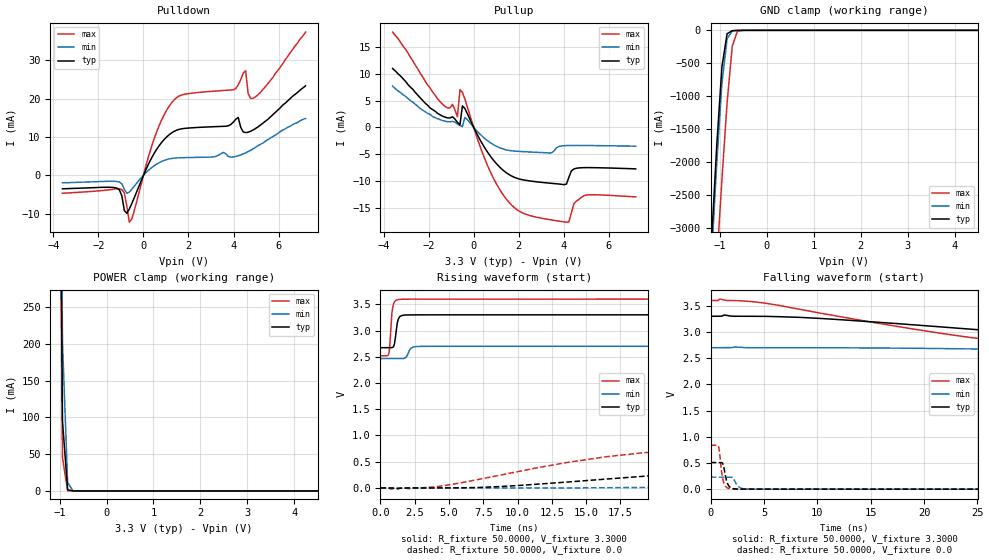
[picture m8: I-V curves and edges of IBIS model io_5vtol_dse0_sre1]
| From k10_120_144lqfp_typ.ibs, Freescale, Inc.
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[Model]  io_5vtol_dse0_sre1
|   Model io_5vtol_dse0_sre1
| Library cells for typ/min/max conditions are connected as defined below:
|  pad - External Pad
|  ipp_do - Core Input
|  ipp_obe - Output Buffer Enable
|  esd_boost - vdd_s_3v
|  esd_bus - vdd_s_3v
|  ipp_ame - vss_s_lv
|  ipp_dse - vss_s_lv
|  ipp_ina40a_5vtol - NC
|  ipp_ina40b_5vtol - NC
|  ipp_ina_5vtol - NC
|  ipp_ina_mux_3v - NC
|  ipp_ind - NC
|  ipp_ind_3v - NC
|  ipp_pue - vss_s_lv
|  ipp_sre - vdd_s_lv
|  tie_3v - vdd_s_3v
|  tie_hi - vdd_s_lv
|  vbuf_3v - vdd_s_3v
|  vdd_bulk_lv - vdd_s_lv
|  vdd_s_3v - vdd_s_3v
|  vdd_s_lv - vdd_s_lv
|  vss_bulk - vss_s_3v
|  vss_s_3v - vss_s_3v
|  vss_s_lv - vss_s_lv
| All other pins connected to ground
Model_type I/O
Polarity   Non-Inverting
Enable   Active-High
Vinl =   1.1550V
Vinh =   2.3100V
Vmeas =  1.6500V
Cref =   25.0000pF
Rref =   50.0000
Vref =   0.0V
C_comp   2.9184pF   2.7887pF   3.0744pF
[Temperature Range]   25.0000   0.1250k   -40.0000
[Voltage Range]   3.3000V   2.7000V   3.6000V
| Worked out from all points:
|   slope of the pulldown table from 0 to 0.495 V, typ, clamps not added: 83.9 ohm
|   slope of the pullup table from 0 to 0.495 V, typ, clamps not added: 129 ohm
|   GND clamp passes 1 mA (typ) near -0.58 V on its own axis
|   POWER clamp passes 1 mA (typ) near -0.79 V on its own axis
|   rising waveform, R_fixture 50.0000, V_fixture 3.3000: 20-80 % time 199ps typ, 277ps min, 174ps max; typ from 2.67 V to 3.3 V
|   rising waveform, R_fixture 50.0000, V_fixture 0.0: 20-80 % time 19.3ns typ, 35.1ns min, 11.9ns max; typ from 0 V to 0.509 V
|   falling waveform, R_fixture 50.0000, V_fixture 3.3000: 20-80 % time 30.8ns typ, 50.7ns min, 22.2ns max; typ from 3.3 V to 2.67 V
|   falling waveform, R_fixture 50.0000, V_fixture 0.0: 20-80 % time 352ps typ, 434ps min, 312ps max; typ from 0.509 V to 0 V
[Pulldown]
|Voltage   I(typ)   I(min)   I(max)
-3.6V     -3.51mA    -1.95mA    -4.66mA
-1.29V    -3.199mA   -1.569mA   -3.563mA
-960mV    -5.372mA   -2.232mA   -3.734mA
-850mV    -9.168mA   -3.652mA   -4.602mA
-630mV    -8.788mA   -4.388mA   -12.21mA
580mV     6.709mA    2.897mA    11.22mA
1.35V     11.41mA    4.463mA    19.56mA
4.21V     15.06mA    5.09mA     23.54mA
4.54V     11.12mA    5.8mA      27.24mA
4.65V     11.23mA    6.2mA      21.29mA
4.87V     11.8mA     6.9mA      20.05mA
7.2V      23.3mA     14.8mA     37.3mA
[Pullup]
|Voltage   I(typ)   I(min)   I(max)
-3.6V     11mA       7.7mA      17.8mA
-1.27V    1.9mA      1.14mA     3.9mA
-720mV    934.8uA    635uA      1.983mA
-610mV    452.4uA    342.8uA    7.026mA
-500mV    4.01mA     137.6uA    6.548mA
-390mV    3.512mA    1.849mA    5.288mA
710mV     -5.2mA     -2.782mA   -8.038mA
1.92V     -9.523mA   -4.475mA   -15.38mA
4.12V     -10.63mA   -3.412mA   -17.73mA
4.34V     -8.156mA   -3.39mA    -16mA
4.89V     -7.539mA   -3.4mA     -12.8mA
7.2V      -7.77mA    -3.53mA    -13mA
[GND_clamp]
|Voltage   I(typ)   I(min)   I(max)
-3.6V     -39.79A    -39.79A    -41.16A
-1.18V    -3.193A    -3.445A    -4.927A
-1.07V    -1.746A    -2.022A    -3.54A
-960mV    -554.7mA   -809.6mA   -2.265A
-850mV    -51.43mA   -127.1mA   -1.104A
-740mV    -5.185mA   -9.693mA   -242.4mA
-630mV    -1.474mA   -1.24mA    -14.98mA
-520mV    -384.8uA   -304.4uA   -1.148mA
7.2V      0A         0A         0A
[POWER_clamp]
|Voltage   I(typ)   I(min)   I(max)
-3.6V     45.62A     45.23A     45.93A
-1.05V    987.4mA    1.121A     927.4mA
-940mV    95.32mA    202.8mA    45.29mA
-830mV    1.645mA    11.46mA    218.1uA
-720mV    22.84uA    474.3uA    919.1nA
-610mV    316.6nA    19.24uA    4.178nA
7.2V      0A         0A         0A
[Ramp]
| variable   typ   min   max
dV/dt_r  0.3054/19.2735n   0.1382/35.0756n   0.5028/11.9407n
dV/dt_f  0.3762/30.7816n   0.1401/50.7335n   0.6486/22.1763n
R_load = 50.0000
[Rising Waveform]
R_fixture= 50.0000
V_fixture= 3.3000
V_fixture_min= 2.7000
V_fixture_max= 3.6000
|time   V(typ)   V(min)   V(max)
0s        2.673V     2.466V     2.519V
604.5ps   2.673V     2.466V     2.556V
681.8ps   2.673V     2.466V     2.719V
833.5ps   2.674V     2.466V     3.33V
967.3ps   2.704V     2.466V     3.516V
1.309ns   3.221V     2.466V     3.591V
1.733ns   3.295V     2.471V     3.597V
2.335ns   3.299V     2.68V      3.598V
3.28ns    3.299V     2.699V     3.599V
250ns     3.3V       2.7V       3.6V
[Rising Waveform]
R_fixture= 50.0000
V_fixture= 0.0
V_fixture_min= 0.0
V_fixture_max= 0.0
|time   V(typ)   V(min)   V(max)
0s        1.227nV    115.8nV    934.1pV
765.5ps   488.2uV    1.713uV    -23.35mV
4.671ns   -71.57uV   -90.98uV   44.8mV
13.5ns    110.4mV    1.034mV    481.1mV
19.03ns   219.4mV    8.822mV    667mV
24.36ns   314mV      25.74mV    759.3mV
31.67ns   401.3mV    57.93mV    812.3mV
49.22ns   489mV      138.4mV    836.5mV
88.94ns   508.7mV    217.1mV    838mV
250ns     509mV      230.4mV    838mV
[Falling Waveform]
R_fixture= 50.0000
V_fixture= 3.3000
V_fixture_min= 2.7000
V_fixture_max= 3.6000
|time   V(typ)   V(min)   V(max)
0s        3.3V       2.7V       3.6V
886ps     3.3V       2.7V       3.628V
4.919ns   3.299V     2.7V       3.555V
18.64ns   3.143V     2.69V      3.068V
29.25ns   2.981V     2.664V     2.78V
37.54ns   2.878V     2.638V     2.661V
49.1ns    2.786V     2.595V     2.589V
70.46ns   2.72V      2.535V     2.542V
100.6ns   2.688V     2.496V     2.524V
250ns     2.673V     2.467V     2.519V
[Falling Waveform]
R_fixture= 50.0000
V_fixture= 0.0
V_fixture_min= 0.0
V_fixture_max= 0.0
|time   V(typ)   V(min)   V(max)
0s        509mV      230.4mV    838mV
726.4ps   509mV      230.4mV    822.2mV
803.7ps   509mV      230.4mV    747.8mV
1.083ns   502.3mV    230.4mV    244.6mV
1.322ns   318.3mV    230.4mV    74.31mV
1.658ns   74.65mV    230.3mV    15.65mV
2.327ns   4.592mV    128.6mV    1.767mV
2.799ns   1.255mV    22.77mV    1.233mV
4.208ns   579.6uV    374.5uV    891.9uV
250ns     41.9nV     118.2nV    8.613nV
